VERSION 5.7 ;
  NOWIREEXTENSIONATPIN ON ;
  DIVIDERCHAR "/" ;
  BUSBITCHARS "[]" ;
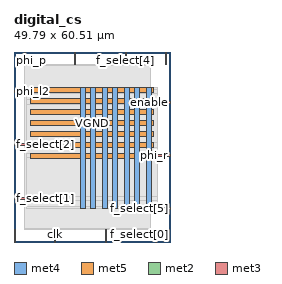
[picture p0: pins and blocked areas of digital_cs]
MACRO digital_cs
  CLASS BLOCK ;
  FOREIGN digital_cs ;
  ORIGIN 0.000 0.000 ;
  SIZE 49.790 BY 60.510 ;
  PIN VGND
    DIRECTION INOUT ;
    USE GROUND ;
    PORT
      LAYER met4 ;
        RECT 24.340 10.640 25.940 49.200 ;
    END
    PORT
      LAYER met4 ;
        RECT 31.340 10.640 32.940 49.200 ;
    END
    PORT
      LAYER met4 ;
        RECT 38.340 10.640 39.940 49.200 ;
    END
    PORT
      LAYER met5 ;
        RECT 5.280 30.030 44.400 31.630 ;
    END
    PORT
      LAYER met5 ;
        RECT 5.280 37.030 44.400 38.630 ;
    END
    PORT
      LAYER met5 ;
        RECT 5.280 44.030 44.400 45.630 ;
    END
  END VGND
  PIN VPWR
    DIRECTION INOUT ;
    USE POWER ;
    PORT
      LAYER met4 ;
        RECT 21.040 10.640 22.640 49.330 ;
    END
    PORT
      LAYER met4 ;
        RECT 28.040 10.640 29.640 49.330 ;
    END
    PORT
      LAYER met4 ;
        RECT 35.040 10.640 36.640 49.330 ;
    END
    PORT
      LAYER met4 ;
        RECT 42.040 10.640 43.640 49.330 ;
    END
    PORT
      LAYER met5 ;
        RECT 5.280 26.730 44.400 28.330 ;
    END
    PORT
      LAYER met5 ;
        RECT 5.280 33.730 44.400 35.330 ;
    END
    PORT
      LAYER met5 ;
        RECT 5.280 40.730 44.400 42.330 ;
    END
    PORT
      LAYER met5 ;
        RECT 5.280 47.730 44.400 49.330 ;
    END
  END VPWR
  PIN clk
    DIRECTION INPUT ;
    USE SIGNAL ;
    PORT
      LAYER met2 ;
        RECT 12.970 0.000 13.250 4.000 ;
    END
  END clk
  PIN enable
    DIRECTION INPUT ;
    USE SIGNAL ;
    PORT
      LAYER met3 ;
        RECT 45.790 44.240 49.790 44.840 ;
    END
  END enable
  PIN f_select[0]
    DIRECTION INPUT ;
    USE SIGNAL ;
    PORT
      LAYER met2 ;
        RECT 45.170 0.000 45.450 4.000 ;
    END
  END f_select[0]
  PIN f_select[1]
    DIRECTION INPUT ;
    USE SIGNAL ;
    PORT
      LAYER met3 ;
        RECT 0.000 13.640 4.000 14.240 ;
    END
  END f_select[1]
  PIN f_select[2]
    DIRECTION INPUT ;
    USE SIGNAL ;
    PORT
      LAYER met3 ;
        RECT 0.000 30.640 4.000 31.240 ;
    END
  END f_select[2]
  PIN f_select[3]
    DIRECTION INPUT ;
    USE SIGNAL ;
    PORT
      LAYER met2 ;
        RECT 0.090 0.000 0.370 4.000 ;
    END
  END f_select[3]
  PIN f_select[4]
    DIRECTION INPUT ;
    USE SIGNAL ;
    PORT
      LAYER met2 ;
        RECT 35.510 56.510 35.790 60.510 ;
    END
  END f_select[4]
  PIN f_select[5]
    DIRECTION INPUT ;
    USE SIGNAL ;
    PORT
      LAYER met3 ;
        RECT 45.790 10.240 49.790 10.840 ;
    END
  END f_select[5]
  PIN f_select[6]
    DIRECTION INPUT ;
    USE SIGNAL ;
    PORT
      LAYER met2 ;
        RECT 19.410 56.510 19.690 60.510 ;
    END
  END f_select[6]
  PIN f_select[7]
    DIRECTION INPUT ;
    USE SIGNAL ;
    PORT
      LAYER met2 ;
        RECT 48.390 56.510 48.670 60.510 ;
    END
  END f_select[7]
  PIN phi_l1
    DIRECTION OUTPUT TRISTATE ;
    USE SIGNAL ;
    PORT
      LAYER met2 ;
        RECT 29.070 0.000 29.350 4.000 ;
    END
  END phi_l1
  PIN phi_l2
    DIRECTION OUTPUT TRISTATE ;
    USE SIGNAL ;
    PORT
      LAYER met3 ;
        RECT 0.000 47.640 4.000 48.240 ;
    END
  END phi_l2
  PIN phi_p
    DIRECTION OUTPUT TRISTATE ;
    USE SIGNAL ;
    PORT
      LAYER met2 ;
        RECT 3.310 56.510 3.590 60.510 ;
    END
  END phi_p
  PIN phi_r
    DIRECTION OUTPUT TRISTATE ;
    USE SIGNAL ;
    PORT
      LAYER met3 ;
        RECT 45.790 27.240 49.790 27.840 ;
    END
  END phi_r
  OBS
      LAYER li1 ;
        RECT 5.520 10.795 44.160 49.045 ;
      LAYER met1 ;
        RECT 3.290 10.640 44.160 49.200 ;
      LAYER met2 ;
        RECT 3.870 56.230 19.130 56.510 ;
        RECT 19.970 56.230 35.230 56.510 ;
        RECT 36.070 56.230 43.610 56.510 ;
        RECT 3.320 4.280 43.610 56.230 ;
        RECT 3.320 4.000 12.690 4.280 ;
        RECT 13.530 4.000 28.790 4.280 ;
        RECT 29.630 4.000 43.610 4.280 ;
      LAYER met3 ;
        RECT 4.000 48.640 45.790 49.125 ;
        RECT 4.400 47.240 45.790 48.640 ;
        RECT 4.000 45.240 45.790 47.240 ;
        RECT 4.000 43.840 45.390 45.240 ;
        RECT 4.000 31.640 45.790 43.840 ;
        RECT 4.400 30.240 45.790 31.640 ;
        RECT 4.000 28.240 45.790 30.240 ;
        RECT 4.000 26.840 45.390 28.240 ;
        RECT 4.000 14.640 45.790 26.840 ;
        RECT 4.400 13.240 45.790 14.640 ;
        RECT 4.000 11.240 45.790 13.240 ;
        RECT 4.000 10.715 45.390 11.240 ;
  END
END digital_cs
END LIBRARY

